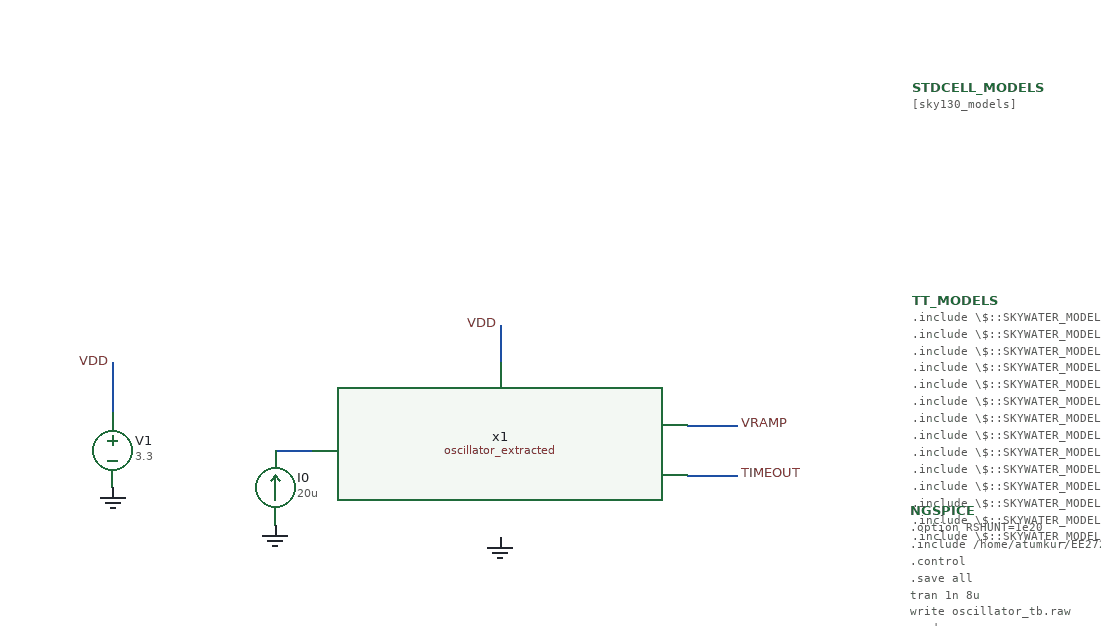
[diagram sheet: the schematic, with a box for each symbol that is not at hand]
v {xschem version=2.9.9 file_version=1.2 }
G {}
K {}
V {}
S {}
E {}
N 70 -270 70 -230 { lab=VDD}
N 380 -300 380 -270 { lab=VDD}
N 200 -200 230 -200 { lab=#net1}
N 530 -220 570 -220 { lab=VRAMP}
N 530 -180 570 -180 { lab=TIMEOUT}
C {devices/vsource.sym} 70 -200 0 0 {name=V1 value=3.3}
C {devices/gnd.sym} 70 -170 0 0 {name=l1 lab=GND}
C {devices/gnd.sym} 380 -130 0 0 {name=l2 lab=GND}
C {devices/lab_pin.sym} 70 -270 0 0 {name=l3 sig_type=std_logic lab=VDD}
C {devices/lab_pin.sym} 380 -300 0 0 {name=l4 sig_type=std_logic lab=VDD}
C {devices/isource.sym} 200 -170 2 0 {name=I0 value=20u}
C {devices/gnd.sym} 200 -140 0 0 {name=l5 lab=GND}
C {devices/lab_pin.sym} 570 -220 0 1 {name=l6 sig_type=std_logic lab=VRAMP}
C {devices/lab_pin.sym} 570 -180 0 1 {name=l7 sig_type=std_logic lab=TIMEOUT}
C {devices/code.sym} 710 -490 0 0 {name=STDCELL_MODELS 
only_toplevel=true
place=end
format="tcleval(@value )"
value="[sky130_models]"
name=s1 only_toplevel=false value=blabla}
C {devices/code.sym} 710 -320 0 0 {name=TT_MODELS
only_toplevel=true
format="tcleval( @value )"
value="
.include \\\\$::SKYWATER_MODELS\\\\/cells/nfet_01v8/sky130_fd_pr__nfet_01v8__tt.corner.spice
.include \\\\$::SKYWATER_MODELS\\\\/cells/nfet_01v8_lvt/sky130_fd_pr__nfet_01v8_lvt__tt.corner.spice
.include \\\\$::SKYWATER_MODELS\\\\/cells/pfet_01v8/sky130_fd_pr__pfet_01v8__tt.corner.spice
.include \\\\$::SKYWATER_MODELS\\\\/cells/nfet_03v3_nvt/sky130_fd_pr__nfet_03v3_nvt__tt.corner.spice
.include \\\\$::SKYWATER_MODELS\\\\/cells/nfet_05v0_nvt/sky130_fd_pr__nfet_05v0_nvt__tt.corner.spice
.include \\\\$::SKYWATER_MODELS\\\\/cells/esd_nfet_01v8/sky130_fd_pr__esd_nfet_01v8__tt.corner.spice
.include \\\\$::SKYWATER_MODELS\\\\/cells/pfet_01v8_lvt/sky130_fd_pr__pfet_01v8_lvt__tt.corner.spice
.include \\\\$::SKYWATER_MODELS\\\\/cells/pfet_01v8_hvt/sky130_fd_pr__pfet_01v8_hvt__tt.corner.spice
.include \\\\$::SKYWATER_MODELS\\\\/cells/esd_pfet_g5v0d10v5/sky130_fd_pr__esd_pfet_g5v0d10v5__tt.corner.spice
.include \\\\$::SKYWATER_MODELS\\\\/cells/pfet_g5v0d10v5/sky130_fd_pr__pfet_g5v0d10v5__tt.corner.spice
.include \\\\$::SKYWATER_MODELS\\\\/cells/pfet_g5v0d16v0/sky130_fd_pr__pfet_g5v0d16v0__tt.corner.spice
.include \\\\$::SKYWATER_MODELS\\\\/cells/nfet_g5v0d10v5/sky130_fd_pr__nfet_g5v0d10v5__tt.corner.spice
.include \\\\$::SKYWATER_MODELS\\\\/cells/nfet_g5v0d16v0/sky130_fd_pr__nfet_g5v0d16v0__tt_discrete.corner.spice
.include \\\\$::SKYWATER_MODELS\\\\/cells/esd_nfet_g5v0d10v5/sky130_fd_pr__esd_nfet_g5v0d10v5__tt.corner.spice
.include \\\\$::SKYWATER_MODELS\\\\/models/corners/tt/nonfet.spice
* Mismatch parameters
.include \\\\$::SKYWATER_MODELS\\\\/cells/nfet_01v8/sky130_fd_pr__nfet_01v8__mismatch.corner.spice
.include \\\\$::SKYWATER_MODELS\\\\/cells/pfet_01v8/sky130_fd_pr__pfet_01v8__mismatch.corner.spice
.include \\\\$::SKYWATER_MODELS\\\\/cells/nfet_01v8_lvt/sky130_fd_pr__nfet_01v8_lvt__mismatch.corner.spice
.include \\\\$::SKYWATER_MODELS\\\\/cells/pfet_01v8_lvt/sky130_fd_pr__pfet_01v8_lvt__mismatch.corner.spice
.include \\\\$::SKYWATER_MODELS\\\\/cells/pfet_01v8_hvt/sky130_fd_pr__pfet_01v8_hvt__mismatch.corner.spice
.include \\\\$::SKYWATER_MODELS\\\\/cells/nfet_g5v0d10v5/sky130_fd_pr__nfet_g5v0d10v5__mismatch.corner.spice
.include \\\\$::SKYWATER_MODELS\\\\/cells/pfet_g5v0d10v5/sky130_fd_pr__pfet_g5v0d10v5__mismatch.corner.spice
.include \\\\$::SKYWATER_MODELS\\\\/cells/nfet_05v0_nvt/sky130_fd_pr__nfet_05v0_nvt__mismatch.corner.spice
.include \\\\$::SKYWATER_MODELS\\\\/cells/nfet_03v3_nvt/sky130_fd_pr__nfet_03v3_nvt__mismatch.corner.spice
* Resistor\\\\$::SKYWATER_MODELS\\\\/Capacitor
.include \\\\$::SKYWATER_MODELS\\\\/models/r+c/res_typical__cap_typical.spice
.include \\\\$::SKYWATER_MODELS\\\\/models/r+c/res_typical__cap_typical__lin.spice
* Special cells
.include \\\\$::SKYWATER_MODELS\\\\/models/corners/tt/specialized_cells.spice
* All models
.include \\\\$::SKYWATER_MODELS\\\\/models/all.spice
* Corner
.include \\\\$::SKYWATER_MODELS\\\\/models/corners/tt/rf.spice
"
}
C {devices/code_shown.sym} 708.75 -151.875 0 0 {name=NGSPICE
only_toplevel=true
value="
.option RSHUNT=1e20
.include /home/atumkur/EE272B/open-pmic/layout/oscillator/oscillator_pex.spice
.control
.save all
tran 1n 8u
write oscillator_tb.raw
.endc
"}
C {layout/oscillator/oscillator_extracted.sym} 380 -200 0 0 {name=x1}
